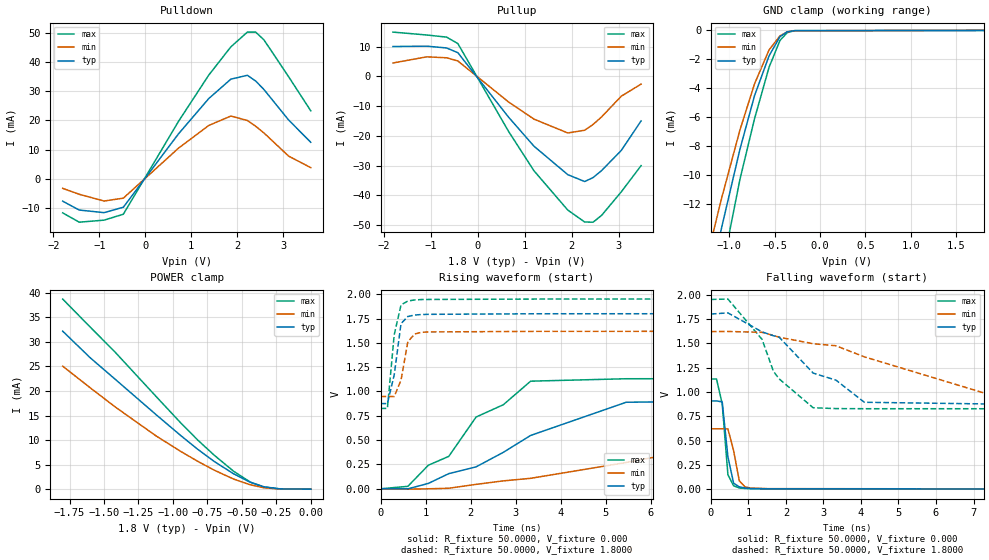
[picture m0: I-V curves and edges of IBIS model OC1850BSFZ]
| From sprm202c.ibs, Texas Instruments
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|   Model OC1850BSFZ
[Model]   OC1850BSFZ
Model_type   3-state
Polarity   Non-Inverting
Enable   Active-Low
Vmeas =   0.9000V
Cref =  15.0000pF
Rref = 100.0000M
Vref =  0.000V
C_comp   1.7520pF   1.7750pF   1.7480pF
[Temperature Range]   25.0000   0.1250k   -40.0000
[Voltage Range]   1.8000V   1.6200V   1.9500V
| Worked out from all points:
|   slope of the pulldown table from 0 to 0.27 V, typ, clamps not added: 45.4 ohm
|   slope of the pullup table from 0 to 0.27 V, typ, clamps not added: 46.7 ohm
|   GND clamp passes 1 mA (typ) near -0.50 V on its own axis
|   POWER clamp passes 1 mA (typ) near -0.40 V on its own axis
|   rising waveform, R_fixture 50.0000, V_fixture 0.000: 20-80 % time 2.69ns typ, 4.09ns min, 1.77ns max; typ from 0 V to 0.907 V
|   rising waveform, R_fixture 50.0000, V_fixture 1.8000: 20-80 % time 184ps typ, 172ps min, 177ps max; typ from 0.875 V to 1.8 V
|   falling waveform, R_fixture 50.0000, V_fixture 0.000: 20-80 % time 190ps typ, 201ps min, 153ps max; typ from 0.907 V to 0 V
|   falling waveform, R_fixture 50.0000, V_fixture 1.8000: 20-80 % time 2.12ns typ, 3.59ns min, 1.38ns max; typ from 1.8 V to 0.875 V
[Pulldown]
| voltage   I(typ)   I(min)   I(max)
-1.8V     -7.807mA   -3.392mA   -11.84mA
-1.44V    -10.87mA   -5.438mA   -15.06mA
-900mV    -11.77mA   -7.766mA   -14.36mA
-480mV    -9.903mA   -6.777mA   -12.32mA
720mV     15.38mA    10.45mA    19.67mA
1.38V     27.57mA    18.29mA    35.66mA
1.86V     34.25mA    21.54mA    45.38mA
2.22V     35.59mA    20mA       50.48mA
2.4V      33.61mA    18.03mA    50.48mA
2.58V     30.7mA     15.71mA    47.82mA
3.12V     20.13mA    7.698mA    35.04mA
3.6V      12.48mA    3.751mA    23.33mA
[Pullup]
| voltage   I(typ)   I(min)   I(max)
-1.8V     10.05mA    4.513mA    14.9mA
-1.08V    10.17mA    6.579mA    13.92mA
-660mV    9.559mA    6.262mA    13.21mA
-420mV    7.99mA     5.205mA    11.06mA
660mV     -13.69mA   -8.592mA   -18.48mA
1.2V      -23.44mA   -14.35mA   -31.7mA
1.92V     -33.02mA   -19.01mA   -44.92mA
2.28V     -35.33mA   -18.09mA   -48.94mA
2.46V     -33.99mA   -16.13mA   -49mA
2.64V     -31.65mA   -13.6mA    -46.71mA
3.06V     -24.86mA   -6.643mA   -38.78mA
3.48V     -14.97mA   -2.586mA   -30mA
[GND_clamp]
| voltage   I(typ)   I(min)   I(max)
-1.8V     -37.91mA   -30.62mA   -43.63mA
-1.6V     -30.48mA   -25.21mA   -34.63mA
-1.48V    -26.12mA   -21.98mA   -29.71mA
-1.28V    -19.37mA   -16.68mA   -23.07mA
-1.08V    -13.6mA    -11.57mA   -16.65mA
-880mV    -8.214mA   -6.883mA   -10.3mA
-720mV    -4.515mA   -3.7mA     -6.112mA
-560mV    -1.758mA   -1.349mA   -2.546mA
-440mV    -433uA     -370.7uA   -690.7uA
-360mV    -90.04uA   -99.21uA   -150.9uA
-280mV    -12.56uA   -20.12uA   -17.67uA
1.8V      13.03nA    8.695uA    2.321nA
[POWER_clamp]
| voltage   I(typ)   I(min)   I(max)
-1.8V     32.18mA    25.05mA    38.72mA
-1.6V     26.76mA    20.64mA    33.01mA
-1.42V    22.41mA    16.77mA    27.92mA
-1.12V    15.12mA    10.8mA     18.81mA
-940mV    10.84mA    7.628mA    13.4mA
-820mV    8.118mA    5.672mA    10mA
-700mV    5.631mA    3.866mA    6.906mA
-560mV    3.131mA    2.058mA    3.655mA
-440mV    1.417mA    901.2uA    1.464mA
-340mV    485.6uA    282.1uA    410.2uA
-220mV    51.85uA    24.45uA    37.83uA
0V        13.03nA    71.9nA     14.93nA
[Ramp]
| variable   typ   min   max
dV/dt_r   0.5433/2.6678n   0.2157/3.0931n   0.6789/1.7685n
dV/dt_f   0.5547/2.1539n   0.3719/3.6433n   0.6740/1.4154n
R_load = 50.0000
[Rising Waveform]
R_fixture = 50.0000
V_fixture = 0.000
V_fixture_min = 0.000
V_fixture_max = 0.000
| time   V(typ)   V(min)   V(max)
0s        9.109uV    8.904uV    8.804uV
606.1ps   -803.7uV   -4.015mV   25.09mV
1.061ns   55.06mV    -225.4uV   242.1mV
1.515ns   155.6mV    5.324mV    333.2mV
2.121ns   225.1mV    45.27mV    737.1mV
2.727ns   374.9mV    81.34mV    864.1mV
3.333ns   548.2mV    107.5mV    1.106V
5.455ns   889.4mV    270.2mV    1.131V
9.091ns   906.7mV    584.9mV    1.132V
15ns      906.8mV    620.3mV    1.132V
[Rising Waveform]
R_fixture = 50.0000
V_fixture = 1.8000
V_fixture_min = 1.6200
V_fixture_max = 1.9500
| time   V(typ)   V(min)   V(max)
0s        875.4mV    948.2mV    826.7mV
151.5ps   875.7mV    948.6mV    825.6mV
303ps     1.17V      948.1mV    1.583V
454.5ps   1.698V     1.117V     1.89V
606.1ps   1.771V     1.512V     1.93V
757.6ps   1.786V     1.591V     1.941V
909.1ps   1.791V     1.608V     1.945V
1.061ns   1.793V     1.612V     1.946V
3.485ns   1.799V     1.618V     1.95V
15ns      1.8V       1.619V     1.95V
[Falling Waveform]
R_fixture = 50.0000
V_fixture = 0.000
V_fixture_min = 0.000
V_fixture_max = 0.000
| time   V(typ)   V(min)   V(max)
0s        906.8mV    620.5mV    1.132V
151.5ps   906.8mV    620.5mV    1.132V
303ps     896.9mV    620.5mV    875.8mV
454.5ps   333.7mV    619.4mV    148.6mV
606.1ps   61.76mV    397.3mV    34.75mV
757.6ps   23.85mV    86.37mV    12.19mV
909.1ps   11.28mV    24.01mV    6.898mV
1.061ns   6.711mV    11.53mV    4.625mV
1.515ns   3.854mV    5.417mV    2.806mV
15ns      32.28uV    556.2uV    10uV
[Falling Waveform]
R_fixture = 50.0000
V_fixture = 1.8000
V_fixture_min = 1.6200
V_fixture_max = 1.9500
| time   V(typ)   V(min)   V(max)
0s        1.8V       1.62V      1.95V
454.5ps   1.812V     1.621V     1.954V
1.364ns   1.617V     1.612V     1.54V
1.667ns   1.577V     1.58V      1.212V
1.818ns   1.563V     1.562V     1.134V
2.727ns   1.193V     1.495V     836.7mV
3.333ns   1.121V     1.474V     828.2mV
4.091ns   893.1mV    1.36V      827mV
7.424ns   875.5mV    972.1mV    826.7mV
15ns      875.4mV    949.5mV    826.7mV
